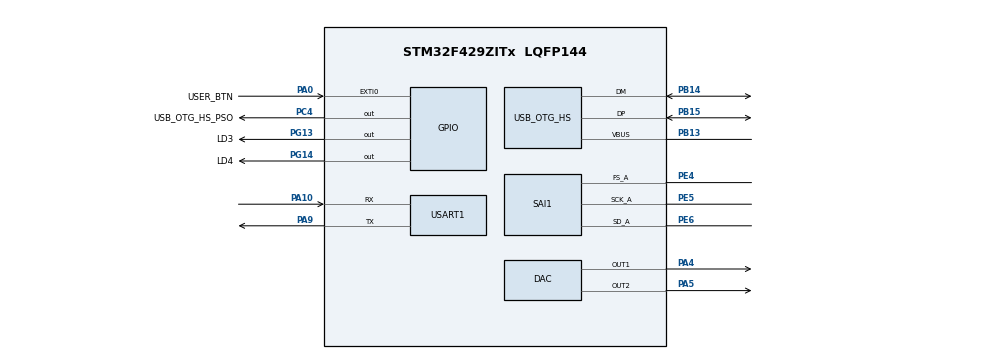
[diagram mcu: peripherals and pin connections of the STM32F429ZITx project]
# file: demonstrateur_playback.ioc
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DAC.DAC_Trigger=DAC_TRIGGER_T2_TRGO
DAC.DAC_Trigger2=DAC_TRIGGER_T2_TRGO
DAC.WaveGeneration=DISABLE
Dma.DAC1.1.Direction=DMA_MEMORY_TO_PERIPH
Dma.DAC1.1.FIFOMode=DMA_FIFOMODE_DISABLE
Dma.DAC1.1.Instance=DMA1_Stream5
Dma.DAC1.1.MemDataAlignment=DMA_MDATAALIGN_HALFWORD
Dma.DAC1.1.MemInc=DMA_MINC_ENABLE
Dma.DAC1.1.Mode=DMA_CIRCULAR
Dma.DAC1.1.PeriphDataAlignment=DMA_PDATAALIGN_HALFWORD
Dma.DAC1.1.PeriphInc=DMA_PINC_DISABLE
Dma.DAC1.1.Priority=DMA_PRIORITY_LOW
Dma.DAC2.2.Direction=DMA_MEMORY_TO_PERIPH
Dma.DAC2.2.FIFOMode=DMA_FIFOMODE_DISABLE
Dma.DAC2.2.Instance=DMA1_Stream6
Dma.DAC2.2.MemDataAlignment=DMA_MDATAALIGN_HALFWORD
Dma.DAC2.2.MemInc=DMA_MINC_ENABLE
Dma.DAC2.2.Mode=DMA_CIRCULAR
Dma.DAC2.2.PeriphDataAlignment=DMA_PDATAALIGN_HALFWORD
Dma.DAC2.2.PeriphInc=DMA_PINC_DISABLE
Dma.DAC2.2.Priority=DMA_PRIORITY_LOW
Dma.Request0=SAI1_A
Dma.Request1=DAC1
Dma.Request2=DAC2
Dma.SAI1_A.0.Direction=DMA_PERIPH_TO_MEMORY
Dma.SAI1_A.0.FIFOMode=DMA_FIFOMODE_DISABLE
Dma.SAI1_A.0.Instance=DMA2_Stream1
Dma.SAI1_A.0.MemDataAlignment=DMA_MDATAALIGN_HALFWORD
Dma.SAI1_A.0.MemInc=DMA_MINC_ENABLE
Dma.SAI1_A.0.Mode=DMA_CIRCULAR
Dma.SAI1_A.0.PeriphDataAlignment=DMA_PDATAALIGN_HALFWORD
Dma.SAI1_A.0.PeriphInc=DMA_PINC_DISABLE
Dma.SAI1_A.0.Priority=DMA_PRIORITY_LOW
FATFS._FS_EXFAT=1
FATFS._MAX_SS=4096
FATFS._USE_LFN=1
Mcu.Family=STM32F4
Mcu.Name=STM32F429ZITx
Mcu.Package=LQFP144
NVIC.DMA1_Stream5_IRQn=true\:0\:0\:false\:false\:true\:false\:true
NVIC.DMA1_Stream6_IRQn=true\:0\:0\:false\:false\:true\:false\:true
NVIC.DMA2_Stream1_IRQn=true\:0\:0\:false\:false\:true\:false\:true
NVIC.OTG_HS_IRQn=true\:0\:0\:false\:false\:true\:false\:true
NVIC.PriorityGroup=NVIC_PRIORITYGROUP_4
NVIC.TIM6_DAC_IRQn=true\:15\:0\:false\:false\:true\:false\:true
NVIC.TimeBase=TIM6_DAC_IRQn
NVIC.TimeBaseIP=TIM6
PA0/WKUP.GPIO_Label=USER_BTN
PA0/WKUP.GPIO_ModeDefaultEXTI=GPIO_MODE_EVT_RISING
PA0/WKUP.Signal=GPXTI0
PA10.Mode=Asynchronous
PA10.Signal=USART1_RX
PA13.Mode=Serial_Wire
PA13.Signal=SYS_JTMS-SWDIO
PA14.Mode=Serial_Wire
PA14.Signal=SYS_JTCK-SWCLK
PA4.Signal=COMP_DAC1_group
PA5.Signal=COMP_DAC2_group
PA9.Mode=Asynchronous
PA9.Signal=USART1_TX
PB13.Mode=Activate_VBUS_FS
PB13.Signal=USB_OTG_HS_VBUS
PB14.Mode=Host_FS
PB14.Signal=USB_OTG_HS_DM
PB15.Mode=Host_FS
PB15.Signal=USB_OTG_HS_DP
PC4.GPIO_Label=USB_OTG_HS_PSO
PC4.Signal=GPIO_Output
PE4.Mode=SAI_A_Master
PE4.Signal=SAI1_FS_A
PE5.Mode=SAI_A_Master
PE5.Signal=SAI1_SCK_A
PE6.Mode=SAI_A_Master
PE6.Signal=SAI1_SD_A
PG13.GPIO_Label=LD3
PG13.Signal=GPIO_Output
PG14.GPIO_Label=LD4
PG14.Signal=GPIO_Output
PH0/OSC_IN.Mode=HSE-External-Oscillator
PH0/OSC_IN.Signal=RCC_OSC_IN
PH1/OSC_OUT.Mode=HSE-External-Oscillator
PH1/OSC_OUT.Signal=RCC_OSC_OUT
ProjectManager.HeapSize=0x200
ProjectManager.StackSize=0x400
ProjectManager.TargetToolchain=STM32CubeIDE
RCC.48MHZClocksFreq_Value=48000000
RCC.AHBFreq_Value=72000000
RCC.APB1CLKDivider=RCC_HCLK_DIV4
RCC.APB1Freq_Value=18000000
RCC.APB1TimFreq_Value=36000000
RCC.APB2CLKDivider=RCC_HCLK_DIV2
RCC.APB2Freq_Value=36000000
RCC.APB2TimFreq_Value=72000000
RCC.CortexFreq_Value=72000000
RCC.HCLKFreq_Value=72000000
RCC.HSE_VALUE=8000000
RCC.HSI_VALUE=16000000
RCC.LSE_VALUE=32768
RCC.PLLI2SN=193
RCC.PLLM=5
RCC.PLLN=90
RCC.PLLQ=3
RCC.PLLSAIN=256
RCC.PLLSAIQ=5
RCC.SYSCLKFreq_VALUE=72000000
RCC.SYSCLKSource=RCC_SYSCLKSOURCE_PLLCLK
RCC.VCOOutputFreq_Value=144000000
SAI1.ActiveFrameLength-SAI_A_Master=32
SAI1.AudioFrequency-SAI_A_Master=SAI_AUDIO_FREQUENCY_32K
SAI1.AudioMode-SAI_A_Master=SAI_MODEMASTER_RX
SAI1.ClockStrobing-SAI_A_Master=SAI_CLOCKSTROBING_RISINGEDGE
SAI1.DataSize-SAI_A_Master=SAI_DATASIZE_16
SAI1.ErrorAudioFreq-SAI_A_Master=0.0 %
SAI1.FSDefinition-SAI_A_Master=SAI_FS_CHANNEL_IDENTIFICATION
SAI1.FrameLength-SAI_A_Master=64
SAI1.Instance-SAI_A_Master=SAI$Index_Block_A
SAI1.MClockEnable-SAI_A_Master=SAI_MASTERCLOCK_DISABLE
SAI1.NoDivider-SAI_A_Master=SAI_MASTERDIVIDER_ENABLE
SAI1.RealAudioFreq-SAI_A_Master=32.0 KHz
SAI1.SlotActive-SAI_A_Master=0x0000FFFF
SAI1.SlotNumber-SAI_A_Master=4
SAI1.Synchro_A=SAI_ASYNCHRONOUS
SAI1.VirtualMode-SAI_A_Master=VM_MASTER
SAI1.VirtualSlotActive-SAI_A_Master=SAI_SLOTACTIVE_ALL
SH.COMP_DAC1_group.0=DAC_OUT1,DAC_OUT1
SH.COMP_DAC2_group.0=DAC_OUT2,DAC_OUT2
TIM2.Period=2249
TIM2.TIM_MasterOutputTrigger=TIM_TRGO_UPDATE
USART1.VirtualMode=VM_ASYNC
USB_HOST.BSP.number=1
USB_HOST.USBH_HandleTypeDef-MSC_HS=hUsbHostHS
USB_HOST.VirtualModeHS=Msc
USB_HOST0.BSP.STBoard=false
USB_HOST0.BSP.api=Unknown
USB_HOST0.BSP.i2caddr=0
USB_HOST0.BSP.instance=PC4
USB_HOST0.BSP.ip=GPIO
USB_HOST0.BSP.mode=Output
USB_HOST0.BSP.name=Drive_VBUS_HS
USB_HOST0.BSP.solution=PC4
USB_OTG_HS.VirtualMode-Host_FS=Host_FS
VP_FATFS_VS_USB.Mode=USB
VP_SYS_VS_tim6.Mode=TIM6
VP_TIM2_VS_ClockSourceINT.Mode=Internal
VP_USB_HOST_VS_USB_HOST_MSC_HS.Mode=MSC_HS
board=custom

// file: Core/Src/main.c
/* USER CODE BEGIN Header */
/**
  ******************************************************************************
  * @file           : main.c
  * @brief          : Main program body
  ******************************************************************************
  * @attention
  *
  * <h2><center>&copy; Copyright (c) 2021 STMicroelectronics.
  * All rights reserved.</center></h2>
  *
  * This software component is licensed by ST under BSD 3-Clause license,
  * the "License"; You may not use this file except in compliance with the
  * License. You may obtain a copy of the License at:
  *                        opensource.org/licenses/BSD-3-Clause
  *
  ******************************************************************************
  */
/* USER CODE END Header */
#include "main.h"

/* USER CODE BEGIN Includes */
#include "pdm_fir.h"
#include <stdlib.h>
#include <string.h>
/* USER CODE END Includes */

/* USER CODE BEGIN PTD */
typedef enum program_state {
    IDLE, RECORDING, PLAYING, SENDING
} program_state;
/* USER CODE END PTD */

/* USER CODE BEGIN PD */
#pragma clang diagnostic push
#pragma ide diagnostic ignored "EndlessLoop"

#define SOUND_FS 32000
#define DECIMATION_FACTOR 64
#define WORD_SIZE 16

#define PDM_BUFFER_SIZE 128
#define PCM_BUFFER_SIZE PDM_BUFFER_SIZE / (DECIMATION_FACTOR / WORD_SIZE) // HERE PCM_BUFFER_SIZE = 128 / (64 / 16) = 32

#define RECORD_TIME 3 // Record Time in Seconds

//#define TRANSMIT
/* USER CODE END PD */

DAC_HandleTypeDef hdac;
DMA_HandleTypeDef hdma_dac1;
DMA_HandleTypeDef hdma_dac2;

SAI_HandleTypeDef hsai_BlockA1;
DMA_HandleTypeDef hdma_sai1_a;

TIM_HandleTypeDef htim2;

UART_HandleTypeDef huart1;

/* USER CODE BEGIN PV */
//declaring Buffers and Buffer Indexes
uint16_t PDM_buffer[PDM_BUFFER_SIZE * 2]; // Double buffer for HALF READ
uint16_t PCM_buffer[PCM_BUFFER_SIZE];
uint16_t PCM_sound[SOUND_FS * RECORD_TIME];
uint32_t pcm_sound_index = 0;

uint32_t sample_count = SOUND_FS * RECORD_TIME;

uint16_t DAC_buffer_left[PCM_BUFFER_SIZE * 2]; // Double buffer for HALF WRITE
uint16_t DAC_buffer_right[PCM_BUFFER_SIZE * 2]; // Double buffer for HALF WRITE

const uint32_t WAVE_HEADER[] = {
        // Declaration fichier
        ('F' << 24) + ('F' << 16) + ('I' << 8) + ('R' << 0), // 'RIFF'
        (SOUND_FS * RECORD_TIME * sizeof(uint16_t)) + 36, // file size + 44 (header) - 8
        ('E' << 24) + ('V' << 16) + ('A' << 8) + ('W' << 0), // WAVE
        (' ' << 24) + ('t' << 16) + ('m' << 8) + ('f' << 0), // 'fmt '
        0x10,
        (1 << 16) + (1 << 0), // PCM Entier + 1 canal
        SOUND_FS, // fs 32kHz
        SOUND_FS * 2, // 32kHz * 2 octet par bloc ech
        (16 << 16) + (2 << 0), // 2 octet par block d'ech et 16 bit par ech
        ('a' << 24) + ('t' << 16) + ('a' << 8) + ('d' << 0), //'data'
        SOUND_FS * RECORD_TIME * sizeof(uint16_t)
};

uint8_t sai_flag = 1, sai_half = 0;
uint8_t dac_flag = 1, dac_half = 0;
/* USER CODE END PV */

void SystemClock_Config(void);

static void MX_GPIO_Init(void);

static void MX_DMA_Init(void);

static void MX_DAC_Init(void);

static void MX_SAI1_Init(void);

static void MX_TIM2_Init(void);

static void MX_USART1_UART_Init(void);

/* USER CODE BEGIN 0 */

// Configuring SAI Interruption Callbacks
void HAL_SAI_RxHalfCpltCallback(SAI_HandleTypeDef *hsai) {
    sai_flag = 0;
    sai_half = 0;
}

void HAL_SAI_RxCpltCallback(SAI_HandleTypeDef *hsai) {
    sai_flag = 0;
    sai_half = 1;
}

// Configuring DAC Interruption Callbacks
void HAL_DAC_ConvHalfCpltCallbackCh1(DAC_HandleTypeDef *hdac1) {
    dac_flag = 0;
    dac_half = 0;
}

void HAL_DAC_ConvCpltCallbackCh1(DAC_HandleTypeDef *hdac1) {
    dac_flag = 0;
    dac_half = 1;
}

// function to Filter a chunk of PDM_DATA
size_t filter_pdm_chunk(struct pdm_fir_filter *filter, uint16_t *pcm_buffer, uint16_t *pdm_buffer, size_t pdm_size,
                        uint16_t decimation, uint16_t linear_gain) {
    uint16_t decimation_words = decimation / WORD_SIZE;
    size_t pcm_to_write = pdm_size / decimation_words;
    for (size_t i = 0; i < pcm_to_write; i++) {
        for (size_t j = 0; j < decimation_words; j++) {
            pdm_fir_flt_put(filter, pdm_buffer[i * decimation_words + j]);
        }
        int32_t received_pcm = pdm_fir_flt_get(filter, 12);
        received_pcm -= 50; // centering PCM Signal
        received_pcm *= linear_gain;
        if (received_pcm > 0x7FF) received_pcm = 0x7FF;
        if (received_pcm < -0x7FF) received_pcm = -0x7FF;
        received_pcm += 0x7FF;
        pcm_buffer[i] = (uint16_t) received_pcm & 0xFFF;
    }
    return pcm_to_write;
}

/* USER CODE END 0 */

int main(void) {
    /* USER CODE BEGIN 1 */
    // Declaring Initial STATE
    program_state current_state = IDLE;
    //declaring pdm_filter
    struct pdm_fir_filter pdm_filter;

    //initializing Buffers
    for (size_t i = 0; i < PDM_BUFFER_SIZE * 2; i++) PDM_buffer[i] = 0;
    for (size_t i = 0; i < PCM_BUFFER_SIZE; i++) PCM_buffer[i] = 0;
    for (size_t i = 0; i < SOUND_FS * RECORD_TIME; i++) PCM_sound[i] = 0x7FF;
    for (size_t i = 0; i < PCM_BUFFER_SIZE * 2; i++) {
        DAC_buffer_left[i] = 0x7FF;
        DAC_buffer_right[i] = 0x7FF;
    }
    /* USER CODE END 1 */

    /* MCU Configuration--------------------------------------------------------*/

    /* Reset of all peripherals, Initializes the Flash interface and the Systick. */
    HAL_Init();

    /* Configure the system clock */
    SystemClock_Config();

    /* Initialize all configured peripherals */
    MX_GPIO_Init();
    MX_DMA_Init();
    MX_DAC_Init();
    MX_SAI1_Init();
    MX_TIM2_Init();
    MX_USART1_UART_Init();
    /* USER CODE BEGIN 2 */

    pdm_fir_flt_init(&pdm_filter);
    HAL_SAI_Receive_DMA(&hsai_BlockA1, (uint8_t *) PDM_buffer, PDM_BUFFER_SIZE * 2);
    HAL_DAC_Start_DMA(&hdac, DAC_CHANNEL_1, (uint32_t *) DAC_buffer_left, PCM_BUFFER_SIZE * 2, DAC_ALIGN_12B_R);
    HAL_DAC_Start_DMA(&hdac, DAC_CHANNEL_2, (uint32_t *) DAC_buffer_right, PCM_BUFFER_SIZE * 2, DAC_ALIGN_12B_R);
    HAL_TIM_Base_Start(&htim2);
    /* USER CODE END 2 */

    /* Infinite loop */
    /* USER CODE BEGIN WHILE */
    uint32_t idle_counter = 0;
    uint16_t cool_down = 0;
    uint32_t play_back_idx = 0, real_idx = 0;
    while (1) {
        /* USER CODE END WHILE */

        /* USER CODE BEGIN 3 */
        switch (current_state) {
            case RECORDING:
                if (!sai_flag) {
                    uint32_t filtered_words = filter_pdm_chunk(&pdm_filter,
                                                               PCM_buffer,
                                                               PDM_buffer + PDM_BUFFER_SIZE * sai_half,
                                                               PDM_BUFFER_SIZE,
                                                               DECIMATION_FACTOR, 9);
                    sai_flag = 1;
                    if (pcm_sound_index + filtered_words > sample_count) {
                        uint32_t available = sample_count - (pcm_sound_index);
                        memcpy(PCM_sound + pcm_sound_index, PCM_buffer, sizeof(uint16_t) * available);
                        memcpy(PCM_sound, PCM_buffer + available, sizeof(uint16_t) * (filtered_words - available));
                    } else {
                        memcpy(PCM_sound + pcm_sound_index, PCM_buffer, sizeof(uint16_t) * filtered_words);
                    }
                    pcm_sound_index = (pcm_sound_index + filtered_words) % sample_count;

                    if (cool_down > 0) cool_down--;
                }
                if (HAL_GPIO_ReadPin(GPIOA, USER_BTN_Pin) == GPIO_PIN_SET && cool_down == 0) {
                    current_state = PLAYING;
                    HAL_GPIO_WritePin(GPIOG, LD3_Pin, GPIO_PIN_SET);
                    HAL_GPIO_WritePin(GPIOG, LD4_Pin, GPIO_PIN_SET);
                }
                break;
            case PLAYING:
                if (!dac_flag) {
                    if (play_back_idx < sample_count) {
                        real_idx = (pcm_sound_index + play_back_idx) % sample_count;
                        if (real_idx + PCM_BUFFER_SIZE > sample_count) {
                            uint32_t available = sample_count - (real_idx);
                            memcpy(DAC_buffer_left + (dac_half * PCM_BUFFER_SIZE), PCM_sound + real_idx,
                                   available * sizeof(uint16_t));
                            memcpy(DAC_buffer_left + (dac_half * PCM_BUFFER_SIZE) + available, PCM_sound,
                                   (PCM_BUFFER_SIZE - available) * sizeof(uint16_t));
                            memcpy(DAC_buffer_right + dac_half * PCM_BUFFER_SIZE,
                                   DAC_buffer_left + dac_half * PCM_BUFFER_SIZE, PCM_BUFFER_SIZE * sizeof(uint16_t));
                        } else {
                            memcpy(DAC_buffer_left + dac_half * PCM_BUFFER_SIZE, PCM_sound + real_idx,
                                   sizeof(uint16_t) * PCM_BUFFER_SIZE);
                            memcpy(DAC_buffer_right + dac_half * PCM_BUFFER_SIZE, PCM_sound + real_idx,
                                   sizeof(uint16_t) * PCM_BUFFER_SIZE);
                        }
                        play_back_idx += PCM_BUFFER_SIZE;
                    } else {
                        play_back_idx = 0;
                        HAL_GPIO_WritePin(GPIOG, LD4_Pin, GPIO_PIN_RESET);
                        HAL_GPIO_WritePin(GPIOG, LD3_Pin, GPIO_PIN_RESET);
                        for (size_t i = 0; i < PCM_BUFFER_SIZE * 2; i++) {
                            DAC_buffer_right[i] = 0x7FF;
                            DAC_buffer_left[i] = 0x7FF;
                        }
#ifdef TRANSMIT
                        current_state = SENDING;
#else
                        current_state = IDLE;
                        cool_down = 250;
                        pcm_sound_index = 0;
#endif
                    }
                    dac_flag = 1;
                }
                break;
            case SENDING:
                HAL_GPIO_WritePin(GPIOG, LD3_Pin, GPIO_PIN_SET);
                HAL_GPIO_WritePin(GPIOG, LD4_Pin, GPIO_PIN_SET);
                // Adding gain on PCM_sound (optimizing sound for 16 bits centered on 0)
                for (size_t i = 0; i < SOUND_FS * RECORD_TIME; i++)
                    PCM_sound[i] = (PCM_sound[i] - 0x7FF) * (0x7FFF / 0x7FF);

                uint16_t bytes_per_send = (sizeof(uint16_t) * SOUND_FS) / 2;  // 0.5s of samples
                uint16_t n_sends = RECORD_TIME * 2;
                // sending FILE HEADER
                HAL_UART_Transmit(&huart1, (uint8_t *) WAVE_HEADER, 44, HAL_MAX_DELAY * 10);
                // sending Data
                for (size_t i = 0; i < n_sends; i++) { // transmit .5s of data @ 115200 Baud on USART1
                    HAL_UART_Transmit(&huart1, (uint8_t *) PCM_sound + i * bytes_per_send,
                                      bytes_per_send, HAL_MAX_DELAY * 10);
                }
                HAL_GPIO_WritePin(GPIOG, LD3_Pin, GPIO_PIN_RESET);
                HAL_GPIO_WritePin(GPIOG, LD4_Pin, GPIO_PIN_RESET);
                current_state = IDLE;
                cool_down = 250;
            case IDLE:
                if (HAL_GPIO_ReadPin(GPIOA, USER_BTN_Pin) == GPIO_PIN_SET && cool_down == 0) {
                    current_state = RECORDING;
                    HAL_GPIO_WritePin(GPIOG, LD3_Pin, GPIO_PIN_SET);
                    HAL_GPIO_WritePin(GPIOG, LD4_Pin, GPIO_PIN_RESET);
                    cool_down = 500;
                }
                if (!sai_flag) { // filtering BUT ignoring output -> Keeping filter up to date
                    (void) filter_pdm_chunk(&pdm_filter, PCM_buffer, PDM_buffer + PDM_BUFFER_SIZE * sai_half,
                                            PDM_BUFFER_SIZE, DECIMATION_FACTOR, 1);
                    sai_flag = 1;
                }
                if (!dac_flag) dac_flag = 1; // resetting DAC flag
                idle_counter = (idle_counter + 1) % 1000000;
                if (cool_down > 0) {
                    cool_down--;
                    HAL_Delay(1);
                } else {
                    HAL_GPIO_WritePin(GPIOG, LD4_Pin, GPIO_PIN_SET);
                }
                break;
            default:
                idle_counter = (idle_counter + 1) % 1000000;
                HAL_GPIO_WritePin(GPIOG, LD3_Pin, GPIO_PIN_SET);
                HAL_GPIO_WritePin(GPIOG, LD3_Pin, GPIO_PIN_SET);
                break;
        }
    }
    /* USER CODE END 3 */
}

void SystemClock_Config(void) {
    RCC_OscInitTypeDef RCC_OscInitStruct = {0};
    RCC_ClkInitTypeDef RCC_ClkInitStruct = {0};

    /** Macro to configure SAI1BlockA clock source selection
    */
    __HAL_RCC_SAI_BLOCKACLKSOURCE_CONFIG(SAI_CLKSOURCE_PLLSAI);
    /** Configure the main internal regulator output voltage
    */
    __HAL_RCC_PWR_CLK_ENABLE();
    __HAL_PWR_VOLTAGESCALING_CONFIG(PWR_REGULATOR_VOLTAGE_SCALE3);
    /** Initializes the RCC Oscillators according to the specified parameters
    * in the RCC_OscInitTypeDef structure.
    */
    RCC_OscInitStruct.OscillatorType = RCC_OSCILLATORTYPE_HSI;
    RCC_OscInitStruct.HSIState = RCC_HSI_ON;
    RCC_OscInitStruct.HSICalibrationValue = RCC_HSICALIBRATION_DEFAULT;
    RCC_OscInitStruct.PLL.PLLState = RCC_PLL_ON;
    RCC_OscInitStruct.PLL.PLLSource = RCC_PLLSOURCE_HSI;
    RCC_OscInitStruct.PLL.PLLM = 10;
    RCC_OscInitStruct.PLL.PLLN = 90;
    RCC_OscInitStruct.PLL.PLLP = RCC_PLLP_DIV2;
    RCC_OscInitStruct.PLL.PLLQ = 4;
    if (HAL_RCC_OscConfig(&RCC_OscInitStruct) != HAL_OK) {
        Error_Handler();
    }
    /** Initializes the CPU, AHB and APB buses clocks
    */
    RCC_ClkInitStruct.ClockType = RCC_CLOCKTYPE_HCLK | RCC_CLOCKTYPE_SYSCLK
                                  | RCC_CLOCKTYPE_PCLK1 | RCC_CLOCKTYPE_PCLK2;
    RCC_ClkInitStruct.SYSCLKSource = RCC_SYSCLKSOURCE_PLLCLK;
    RCC_ClkInitStruct.AHBCLKDivider = RCC_SYSCLK_DIV1;
    RCC_ClkInitStruct.APB1CLKDivider = RCC_HCLK_DIV2;
    RCC_ClkInitStruct.APB2CLKDivider = RCC_HCLK_DIV1;

    if (HAL_RCC_ClockConfig(&RCC_ClkInitStruct, FLASH_LATENCY_2) != HAL_OK) {
        Error_Handler();
    }
}

static void MX_DAC_Init(void) {

    DAC_ChannelConfTypeDef sConfig = {0};

    /** DAC Initialization
    */
    hdac.Instance = DAC;
    if (HAL_DAC_Init(&hdac) != HAL_OK) {
        Error_Handler();
    }
    /** DAC channel OUT1 config
    */
    sConfig.DAC_Trigger = DAC_TRIGGER_T2_TRGO;
    sConfig.DAC_OutputBuffer = DAC_OUTPUTBUFFER_ENABLE;
    if (HAL_DAC_ConfigChannel(&hdac, &sConfig, DAC_CHANNEL_1) != HAL_OK) {
        Error_Handler();
    }
    /** DAC channel OUT2 config
    */
    if (HAL_DAC_ConfigChannel(&hdac, &sConfig, DAC_CHANNEL_2) != HAL_OK) {
        Error_Handler();
    }

}

static void MX_SAI1_Init(void) {

    hsai_BlockA1.Instance = SAI1_Block_A;
    hsai_BlockA1.Init.Protocol = SAI_FREE_PROTOCOL;
    hsai_BlockA1.Init.AudioMode = SAI_MODEMASTER_RX;
    hsai_BlockA1.Init.DataSize = SAI_DATASIZE_16;
    hsai_BlockA1.Init.FirstBit = SAI_FIRSTBIT_MSB;
    hsai_BlockA1.Init.ClockStrobing = SAI_CLOCKSTROBING_RISINGEDGE;
    hsai_BlockA1.Init.Synchro = SAI_ASYNCHRONOUS;
    hsai_BlockA1.Init.OutputDrive = SAI_OUTPUTDRIVE_DISABLE;
    hsai_BlockA1.Init.NoDivider = SAI_MASTERDIVIDER_ENABLE;
    hsai_BlockA1.Init.FIFOThreshold = SAI_FIFOTHRESHOLD_EMPTY;
    hsai_BlockA1.Init.ClockSource = SAI_CLKSOURCE_PLLSAI;
    hsai_BlockA1.Init.AudioFrequency = SAI_AUDIO_FREQUENCY_32K;
    hsai_BlockA1.FrameInit.FrameLength = 64;
    hsai_BlockA1.FrameInit.ActiveFrameLength = 32;
    hsai_BlockA1.FrameInit.FSDefinition = SAI_FS_CHANNEL_IDENTIFICATION;
    hsai_BlockA1.FrameInit.FSPolarity = SAI_FS_ACTIVE_LOW;
    hsai_BlockA1.FrameInit.FSOffset = SAI_FS_FIRSTBIT;
    hsai_BlockA1.SlotInit.FirstBitOffset = 0;
    hsai_BlockA1.SlotInit.SlotSize = SAI_SLOTSIZE_DATASIZE;
    hsai_BlockA1.SlotInit.SlotNumber = 4;
    hsai_BlockA1.SlotInit.SlotActive = 0x0000FFFF;
    if (HAL_SAI_Init(&hsai_BlockA1) != HAL_OK) {
        Error_Handler();
    }

}

static void MX_TIM2_Init(void) {

    TIM_ClockConfigTypeDef sClockSourceConfig = {0};
    TIM_MasterConfigTypeDef sMasterConfig = {0};

    htim2.Instance = TIM2;
    htim2.Init.Prescaler = 0;
    htim2.Init.CounterMode = TIM_COUNTERMODE_UP;
    htim2.Init.Period = 2249;
    htim2.Init.ClockDivision = TIM_CLOCKDIVISION_DIV1;
    htim2.Init.AutoReloadPreload = TIM_AUTORELOAD_PRELOAD_DISABLE;
    if (HAL_TIM_Base_Init(&htim2) != HAL_OK) {
        Error_Handler();
    }
    sClockSourceConfig.ClockSource = TIM_CLOCKSOURCE_INTERNAL;
    if (HAL_TIM_ConfigClockSource(&htim2, &sClockSourceConfig) != HAL_OK) {
        Error_Handler();
    }
    sMasterConfig.MasterOutputTrigger = TIM_TRGO_UPDATE;
    sMasterConfig.MasterSlaveMode = TIM_MASTERSLAVEMODE_DISABLE;
    if (HAL_TIMEx_MasterConfigSynchronization(&htim2, &sMasterConfig) != HAL_OK) {
        Error_Handler();
    }

}

static void MX_USART1_UART_Init(void) {

    huart1.Instance = USART1;
    huart1.Init.BaudRate = 115200;
    huart1.Init.WordLength = UART_WORDLENGTH_8B;
    huart1.Init.StopBits = UART_STOPBITS_1;
    huart1.Init.Parity = UART_PARITY_NONE;
    huart1.Init.Mode = UART_MODE_TX_RX;
    huart1.Init.HwFlowCtl = UART_HWCONTROL_NONE;
    huart1.Init.OverSampling = UART_OVERSAMPLING_16;
    if (HAL_UART_Init(&huart1) != HAL_OK) {
        Error_Handler();
    }

}

static void MX_DMA_Init(void) {

    /* DMA controller clock enable */
    __HAL_RCC_DMA2_CLK_ENABLE();
    __HAL_RCC_DMA1_CLK_ENABLE();

    /* DMA interrupt init */
    /* DMA1_Stream5_IRQn interrupt configuration */
    HAL_NVIC_SetPriority(DMA1_Stream5_IRQn, 0, 0);
    HAL_NVIC_EnableIRQ(DMA1_Stream5_IRQn);
    /* DMA1_Stream6_IRQn interrupt configuration */
    HAL_NVIC_SetPriority(DMA1_Stream6_IRQn, 0, 0);
    HAL_NVIC_EnableIRQ(DMA1_Stream6_IRQn);
    /* DMA2_Stream1_IRQn interrupt configuration */
    HAL_NVIC_SetPriority(DMA2_Stream1_IRQn, 0, 0);
    HAL_NVIC_EnableIRQ(DMA2_Stream1_IRQn);

}

static void MX_GPIO_Init(void) {
    GPIO_InitTypeDef GPIO_InitStruct = {0};

    /* GPIO Ports Clock Enable */
    __HAL_RCC_GPIOE_CLK_ENABLE();
    __HAL_RCC_GPIOH_CLK_ENABLE();
    __HAL_RCC_GPIOA_CLK_ENABLE();
    __HAL_RCC_GPIOG_CLK_ENABLE();

    /*Configure GPIO pin Output Level */
    HAL_GPIO_WritePin(GPIOG, LD3_Pin | LD4_Pin, GPIO_PIN_RESET);

    /*Configure GPIO pin : USER_BTN_Pin */
    GPIO_InitStruct.Pin = USER_BTN_Pin;
    GPIO_InitStruct.Mode = GPIO_MODE_EVT_RISING;
    GPIO_InitStruct.Pull = GPIO_NOPULL;
    HAL_GPIO_Init(USER_BTN_GPIO_Port, &GPIO_InitStruct);

    /*Configure GPIO pins : LD3_Pin LD4_Pin */
    GPIO_InitStruct.Pin = LD3_Pin | LD4_Pin;
    GPIO_InitStruct.Mode = GPIO_MODE_OUTPUT_PP;
    GPIO_InitStruct.Pull = GPIO_NOPULL;
    GPIO_InitStruct.Speed = GPIO_SPEED_FREQ_LOW;
    HAL_GPIO_Init(GPIOG, &GPIO_InitStruct);

}

void HAL_TIM_PeriodElapsedCallback(TIM_HandleTypeDef *htim) {
    if (htim->Instance == TIM6) {
        HAL_IncTick();
    }
}

void Error_Handler(void) {
    __disable_irq();
    while (1) {
    }
}

/************************ (C) COPYRIGHT STMicroelectronics *****END OF FILE****/
